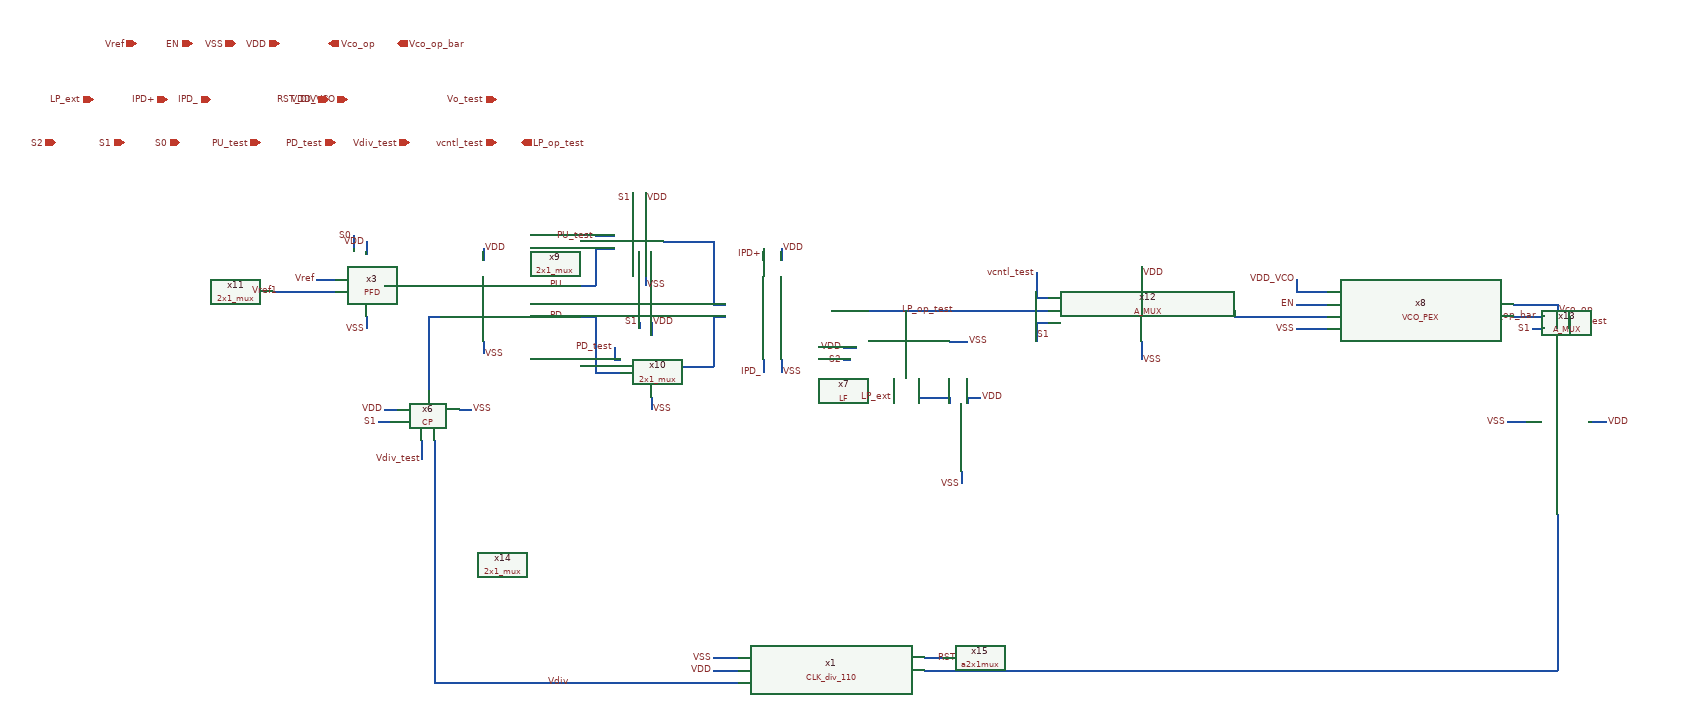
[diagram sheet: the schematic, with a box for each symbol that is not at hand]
v {xschem version=3.1.0 file_version=1.2
}
G {}
K {}
V {}
S {}
E {}
N 830 -810 830 -790 {
lab=VDD}
N 830 -660 830 -640 {
lab=VSS}
N 740 -750 760 -750 {
lab=#net1}
N 740 -700 760 -700 {
lab=#net2}
N 900 -700 920 -700 {
lab=PD}
N 920 -750 1010 -750 {
lab=PU}
N 920 -700 1010 -700 {
lab=PD}
N 950 -110 1240 -110 {
lab=Vdiv}
N 2140 -740 2180 -740 {
lab=VDD_VCO}
N 900 -750 920 -750 {
lab=PU}
N 2140 -760 2140 -740 {
lab=VDD_VCO}
N 1200 -150 1240 -150 {
lab=VSS}
N 1200 -130 1240 -130 {
lab=VDD}
N 1540 -130 1570 -130 {
lab=#net3}
N 1540 -150 1570 -150 {
lab=RST_DIV}
N 2180 -740 2190 -740 {
lab=VDD_VCO}
N 1310 -810 1310 -790 {
lab=VDD}
N 1310 -630 1310 -610 {
lab=VSS}
N 1200 -720 1220 -720 {
lab=#net4}
N 1200 -700 1220 -700 {
lab=#net5}
N 1280 -810 1280 -790 {
lab=IPD+}
N 1280 -630 1280 -610 {
lab=IPD_}
N 510 -740 540 -740 {
lab=Vref1}
N 490 -740 510 -740 {
lab=Vref1}
N 1010 -700 1010 -610 {
lab=PD}
N 1010 -610 1050 -610 {
lab=PD}
N 1040 -630 1050 -630 {
lab=PD_test}
N 1040 -650 1040 -630 {
lab=PD_test}
N 1010 -810 1010 -750 {
lab=PU}
N 1010 -810 1040 -810 {
lab=PU}
N 1090 -770 1090 -750 {
lab=VSS}
N 1080 -690 1080 -680 {
lab=S1}
N 1100 -690 1100 -670 {
lab=VDD}
N 1120 -820 1200 -820 {
lab=#net4}
N 1200 -820 1200 -750 {
lab=#net4}
N 1200 -700 1200 -620 {
lab=#net5}
N 1130 -620 1200 -620 {
lab=#net5}
N 1200 -750 1200 -720 {
lab=#net4}
N 1070 -900 1070 -880 {
lab=S1}
N 1090 -900 1090 -870 {
lab=VDD}
N 1010 -830 1040 -830 {
lab=PU_test}
N 1100 -570 1100 -550 {
lab=VSS}
N 640 -700 640 -680 {
lab=VSS}
N 640 -820 640 -800 {
lab=VDD}
N 620 -830 620 -810 {
lab=S0}
N 540 -740 590 -740 {
lab=Vref1}
N 560 -760 590 -760 {
lab=Vref}
N 1890 -780 1890 -760 {
lab=VDD}
N 1890 -660 1890 -630 {
lab=VSS}
N 1720 -730 1740 -730 {
lab=vcntl_test}
N 1720 -770 1720 -730 {
lab=vcntl_test}
N 1720 -690 1740 -690 {
lab=S1}
N 1720 -690 1720 -660 {
lab=S1}
N 2580 -700 2580 -680 {
lab=Vo_test}
N 2480 -530 2510 -530 {
lab=VSS}
N 2610 -530 2640 -530 {
lab=VDD}
N 2520 -680 2540 -680 {
lab=S1}
N 2040 -700 2190 -700 {
lab=#net6}
N 2040 -710 2040 -700 {
lab=#net6}
N 2140 -720 2190 -720 {
lab=EN}
N 2140 -680 2190 -680 {
lab=VSS}
N 2490 -720 2560 -720 {
lab=Vco_op}
N 2490 -700 2540 -700 {
lab=Vco_op_bar}
N 2560 -720 2560 -680 {
lab=Vco_op}
N 670 -750 730 -750 {
lab=#net1}
N 790 -550 810 -550 {
lab=VSS}
N 670 -550 690 -550 {
lab=VDD}
N 660 -530 680 -530 {
lab=S1}
N 750 -500 750 -450 {
lab=Vdiv}
N 730 -500 730 -470 {
lab=Vdiv_test}
N 740 -640 740 -580 {
lab=#net2}
N 750 -450 750 -400 {
lab=Vdiv}
N 740 -700 740 -640 {
lab=#net2}
N 730 -750 740 -750 {
lab=#net1}
N 1600 -450 1600 -430 {
lab=VSS}
N 1610 -570 1610 -560 {
lab=VDD}
N 1610 -570 1630 -570 {
lab=VDD}
N 1410 -650 1430 -650 {
lab=VDD}
N 1580 -660 1610 -660 {
lab=VSS}
N 1490 -600 1490 -570 {
lab=LP_ext}
N 1580 -570 1580 -560 {
lab=#net7}
N 1530 -570 1580 -570 {
lab=#net7}
N 1530 -600 1530 -570 {
lab=#net7}
N 1510 -710 1510 -700 {
lab=LP_op_test}
N 750 -110 950 -110 {
lab=Vdiv}
N 750 -400 750 -280 {
lab=Vdiv}
N 750 -280 750 -110 {
lab=Vdiv}
N 2560 -380 2560 -220 {
lab=#net3}
N 2560 -220 2560 -210 {
lab=#net3}
N 1410 -630 1420 -630 {
lab=S2}
N 1390 -710 1740 -710 {
lab=LP_op_test}
N 1570 -130 2560 -130 {
lab=#net3}
N 2560 -210 2560 -130 {
lab=#net3}
C {PFD.sym} 540 -540 0 0 {name=x3}
C {devices/lab_pin.sym} 830 -810 2 0 {name=p9 sig_type=std_logic lab=VDD}
C {devices/lab_wire.sym} 830 -640 2 0 {name=p10 sig_type=std_logic lab=VSS}
C {devices/lab_pin.sym} 970 -110 1 0 {name=p28 sig_type=std_logic lab=Vdiv
}
C {devices/lab_pin.sym} 2140 -760 0 0 {name=p12 sig_type=std_logic lab=VDD_VCO}
C {devices/lab_pin.sym} 2530 -700 1 0 {name=p13 sig_type=std_logic lab=Vco_op_bar
}
C {devices/lab_pin.sym} 1200 -130 0 0 {name=p14 sig_type=std_logic lab=VDD}
C {devices/lab_wire.sym} 1200 -150 1 0 {name=p15 sig_type=std_logic lab=VSS}
C {devices/lab_pin.sym} 1590 -710 1 0 {name=p19 sig_type=std_logic lab=LP_op_test
}
C {devices/lab_pin.sym} 960 -750 1 0 {name=p20 sig_type=std_logic lab=PU}
C {devices/lab_pin.sym} 960 -700 1 0 {name=p21 sig_type=std_logic lab=PD}
C {devices/lab_pin.sym} 1560 -150 2 0 {name=p39 sig_type=std_logic lab=RST_DIV}
C {devices/lab_wire.sym} 1310 -610 2 0 {name=p49 sig_type=std_logic lab=VSS}
C {devices/lab_pin.sym} 1310 -810 2 0 {name=p50 sig_type=std_logic lab=VDD}
C {CP.sym} 730 -510 0 0 {name=x6}
C {devices/lab_wire.sym} 1280 -800 0 0 {name=p52 sig_type=std_logic lab=IPD+}
C {devices/lab_wire.sym} 1280 -610 0 0 {name=p53 sig_type=std_logic lab=IPD_}
C {2x1_mux.sym} 840 -700 0 0 {name=x9}
C {2x1_mux.sym} 850 -500 0 0 {name=x10}
C {devices/lab_pin.sym} 1010 -830 0 0 {name=p60 sig_type=std_logic lab=PU_test
}
C {devices/lab_pin.sym} 1040 -650 1 0 {name=p61 sig_type=std_logic lab=PD_test
}
C {devices/lab_pin.sym} 1090 -890 2 0 {name=p62 sig_type=std_logic lab=VDD}
C {devices/lab_pin.sym} 1100 -690 2 0 {name=p63 sig_type=std_logic lab=VDD}
C {devices/lab_wire.sym} 1100 -550 2 0 {name=p64 sig_type=std_logic lab=VSS}
C {devices/lab_wire.sym} 1090 -750 2 0 {name=p65 sig_type=std_logic lab=VSS}
C {devices/lab_pin.sym} 1070 -890 1 0 {name=p106 sig_type=std_logic lab=S1}
C {devices/lab_pin.sym} 1080 -690 1 0 {name=p66 sig_type=std_logic lab=S1}
C {2x1_mux.sym} 390 -630 0 0 {name=x11}
C {devices/lab_wire.sym} 640 -680 3 0 {name=p67 sig_type=std_logic lab=VSS}
C {devices/lab_pin.sym} 640 -820 3 1 {name=p68 sig_type=std_logic lab=VDD}
C {devices/lab_pin.sym} 620 -830 1 0 {name=p69 sig_type=std_logic lab=S0}
C {devices/lab_pin.sym} 560 -760 1 0 {name=p70 sig_type=std_logic lab=Vref
}
C {A_MUX.sym} 1890 -710 0 0 {name=x12}
C {devices/lab_pin.sym} 1890 -770 2 0 {name=p73 sig_type=std_logic lab=VDD}
C {devices/lab_wire.sym} 1890 -630 2 0 {name=p74 sig_type=std_logic lab=VSS}
C {devices/lab_pin.sym} 1720 -670 2 0 {name=p75 sig_type=std_logic lab=S1}
C {devices/lab_pin.sym} 1720 -770 0 0 {name=p76 sig_type=std_logic lab=vcntl_test
}
C {devices/lab_pin.sym} 2560 -710 2 0 {name=p77 sig_type=std_logic lab=Vco_op
}
C {devices/lab_pin.sym} 2580 -690 2 0 {name=p78 sig_type=std_logic lab=Vo_test
}
C {A_MUX.sym} 2560 -530 1 0 {name=x13}
C {devices/lab_pin.sym} 2520 -680 0 0 {name=p79 sig_type=std_logic lab=S1}
C {devices/lab_wire.sym} 2480 -530 0 0 {name=p36 sig_type=std_logic lab=VSS}
C {devices/lab_pin.sym} 2640 -530 2 0 {name=p80 sig_type=std_logic lab=VDD}
C {VCO_PEX.sym} 2340 -710 0 0 {name=x8}
C {devices/lab_pin.sym} 2140 -720 0 0 {name=p81 sig_type=std_logic lab=EN}
C {devices/lab_wire.sym} 2140 -680 2 1 {name=p89 sig_type=std_logic lab=VSS}
C {2x1_mux.sym} 860 -300 3 0 {name=x14}
C {devices/lab_wire.sym} 810 -550 2 0 {name=p91 sig_type=std_logic lab=VSS}
C {devices/lab_pin.sym} 670 -550 2 1 {name=p92 sig_type=std_logic lab=VDD}
C {devices/lab_pin.sym} 660 -530 0 0 {name=p93 sig_type=std_logic lab=S1}
C {devices/lab_pin.sym} 730 -470 0 0 {name=p94 sig_type=std_logic lab=Vdiv_test

}
C {devices/lab_wire.sym} 1600 -430 2 1 {name=p58 sig_type=std_logic lab=VSS}
C {devices/lab_wire.sym} 1630 -570 0 1 {name=p98 sig_type=std_logic lab=VDD}
C {devices/lab_wire.sym} 1610 -660 2 0 {name=p99 sig_type=std_logic lab=VSS}
C {devices/lab_wire.sym} 1410 -650 2 1 {name=p100 sig_type=std_logic lab=VDD}
C {devices/lab_wire.sym} 1410 -630 1 1 {name=p101 sig_type=std_logic lab=S2}
C {LF.sym} 1740 -400 0 1 {name=x7}
C {a2x1mux.sym} 1670 -280 3 0 {name=x15}
C {CLK_div_110.sym} 1390 -130 0 1 {name=x1}
C {devices/iopin.sym} 430 -1140 0 0 {name=p22 lab=VSS
}
C {devices/iopin.sym} 500 -1140 0 0 {name=p23 lab=VDD}
C {devices/opin.sym} 580 -1140 0 0 {name=p24 lab=Vco_op}
C {devices/ipin.sym} 140 -980 0 0 {name=p32 lab=S2}
C {devices/ipin.sym} 270 -1140 0 0 {name=p33 lab=Vref}
C {devices/opin.sym} 690 -1140 0 0 {name=p34 lab=Vco_op_bar}
C {devices/iopin.sym} 610 -1050 0 0 {name=p35 lab=VDD_VCO}
C {devices/ipin.sym} 580 -1050 0 0 {name=p37 lab=RST_DIV}
C {devices/iopin.sym} 320 -1050 0 0 {name=p40 lab=IPD+
}
C {devices/iopin.sym} 390 -1050 0 0 {name=p82 lab=IPD_}
C {devices/ipin.sym} 360 -1140 0 0 {name=p83 lab=EN}
C {devices/iopin.sym} 200 -1050 0 0 {name=p84 lab=LP_ext
}
C {devices/ipin.sym} 250 -980 0 0 {name=p85 lab=S1}
C {devices/ipin.sym} 340 -980 0 0 {name=p86 lab=S0}
C {devices/lab_pin.sym} 1490 -570 0 0 {name=p87 sig_type=std_logic lab=LP_ext
}
C {devices/ipin.sym} 470 -980 0 0 {name=p88 lab=PU_test}
C {devices/ipin.sym} 590 -980 0 0 {name=p90 lab=PD_test}
C {devices/ipin.sym} 710 -980 0 0 {name=p97 lab=Vdiv_test}
C {devices/ipin.sym} 850 -980 0 0 {name=p102 lab=vcntl_test}
C {devices/ipin.sym} 850 -1050 0 0 {name=p103 lab=Vo_test}
C {devices/opin.sym} 890 -980 0 0 {name=p104 lab=LP_op_test}
C {devices/lab_pin.sym} 500 -740 1 0 {name=p105 sig_type=std_logic lab=Vref1
}
